VERSION 5.7 ;
  NOWIREEXTENSIONATPIN ON ;
  DIVIDERCHAR "/" ;
  BUSBITCHARS "[]" ;
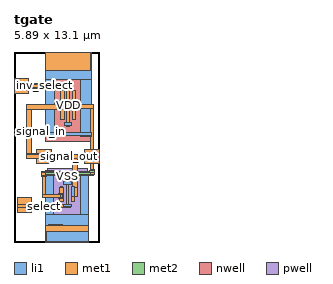
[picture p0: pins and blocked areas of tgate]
MACRO tgate
  CLASS BLOCK ;
  FOREIGN tgate ;
  ORIGIN 0.000 9.990 ;
  SIZE 5.890 BY 13.100 ;
  PIN inv_select
    ANTENNAGATEAREA 1.000000 ;
    PORT
      LAYER li1 ;
        RECT 3.480 0.690 3.980 0.860 ;
        RECT 3.480 -1.950 3.980 -1.780 ;
      LAYER met1 ;
        RECT 0.000 0.945 1.000 1.270 ;
        RECT 0.000 0.890 3.825 0.945 ;
        RECT 0.000 0.660 3.960 0.890 ;
        RECT 0.000 0.595 3.840 0.660 ;
        RECT 0.000 0.270 1.000 0.595 ;
        RECT 3.610 -1.750 3.840 0.595 ;
        RECT 3.500 -1.980 3.960 -1.750 ;
        RECT 3.610 -2.010 3.840 -1.980 ;
    END
  END inv_select
  PIN signal_in
    ANTENNADIFFAREA 0.870000 ;
    PORT
      LAYER li1 ;
        RECT 3.250 -1.565 3.420 0.475 ;
        RECT 3.990 -7.230 4.160 -6.190 ;
      LAYER met1 ;
        RECT 3.220 -0.495 3.450 0.455 ;
        RECT 0.885 -0.850 3.450 -0.495 ;
        RECT 0.885 -3.910 1.240 -0.850 ;
        RECT 3.220 -1.545 3.450 -0.850 ;
        RECT 1.570 -3.910 2.570 -3.590 ;
        RECT 0.885 -3.940 2.570 -3.910 ;
        RECT 0.885 -4.240 4.350 -3.940 ;
        RECT 0.885 -4.265 2.570 -4.240 ;
        RECT 1.570 -4.590 2.570 -4.265 ;
        RECT 4.050 -6.210 4.350 -4.240 ;
        RECT 3.960 -6.850 4.350 -6.210 ;
        RECT 3.960 -7.210 4.190 -6.850 ;
    END
  END signal_in
  PIN signal_out
    ANTENNADIFFAREA 0.870000 ;
    PORT
      LAYER li1 ;
        RECT 4.040 -1.565 4.210 0.475 ;
        RECT 3.200 -7.230 3.370 -6.190 ;
      LAYER met1 ;
        RECT 4.010 -0.505 4.240 0.455 ;
        RECT 4.010 -0.755 5.515 -0.505 ;
        RECT 4.010 -1.545 4.240 -0.755 ;
        RECT 5.265 -3.600 5.515 -0.755 ;
        RECT 4.890 -4.600 5.890 -3.600 ;
        RECT 5.295 -5.025 5.490 -4.600 ;
        RECT 1.920 -5.470 2.180 -5.150 ;
        RECT 5.265 -5.345 5.525 -5.025 ;
        RECT 1.950 -6.725 2.150 -5.470 ;
        RECT 3.170 -6.670 3.400 -6.210 ;
        RECT 3.070 -6.725 3.400 -6.670 ;
        RECT 1.950 -6.925 3.400 -6.725 ;
        RECT 3.070 -6.980 3.400 -6.925 ;
        RECT 3.170 -7.210 3.400 -6.980 ;
      LAYER met2 ;
        RECT 1.890 -5.210 2.210 -5.180 ;
        RECT 5.235 -5.210 5.555 -5.055 ;
        RECT 1.890 -5.315 5.555 -5.210 ;
        RECT 1.890 -5.410 5.480 -5.315 ;
        RECT 1.890 -5.440 2.210 -5.410 ;
    END
  END signal_out
  PIN select
    ANTENNAGATEAREA 0.500000 ;
    PORT
      LAYER li1 ;
        RECT 3.430 -6.020 3.930 -5.850 ;
        RECT 3.430 -7.570 3.930 -7.400 ;
      LAYER met1 ;
        RECT 3.450 -6.050 3.910 -5.820 ;
        RECT 0.220 -7.405 1.220 -6.930 ;
        RECT 3.620 -7.370 3.760 -6.050 ;
        RECT 3.450 -7.405 3.910 -7.370 ;
        RECT 0.220 -7.635 3.915 -7.405 ;
        RECT 0.220 -7.930 1.220 -7.635 ;
    END
  END select
  PIN VDD
    ANTENNADIFFAREA 3.567000 ;
    PORT
      LAYER nwell ;
        RECT 2.190 -3.030 5.270 1.940 ;
      LAYER li1 ;
        RECT 2.150 1.240 5.350 3.100 ;
        RECT 2.150 -2.470 2.790 1.240 ;
        RECT 4.580 -2.470 5.350 1.240 ;
        RECT 2.150 -2.640 5.350 -2.470 ;
        RECT 2.150 -2.730 2.790 -2.640 ;
        RECT 4.580 -2.700 5.350 -2.640 ;
        RECT 2.270 -2.750 2.790 -2.730 ;
        RECT 2.460 -2.760 2.790 -2.750 ;
      LAYER met1 ;
        RECT 2.140 1.820 5.300 3.110 ;
    END
  END VDD
  PIN VSS
    ANTENNADIFFAREA 2.946400 ;
    PORT
      LAYER pwell ;
        RECT 2.280 -8.500 5.080 -4.920 ;
      LAYER li1 ;
        RECT 2.200 -5.160 2.730 -5.060 ;
        RECT 4.610 -5.160 5.140 -5.100 ;
        RECT 2.200 -5.330 5.140 -5.160 ;
        RECT 2.200 -8.090 2.730 -5.330 ;
        RECT 4.610 -8.090 5.140 -5.330 ;
        RECT 2.200 -9.250 5.140 -8.090 ;
        RECT 2.210 -9.980 5.140 -9.250 ;
      LAYER met1 ;
        RECT 2.370 -8.870 3.370 -8.810 ;
        RECT 2.170 -9.990 5.140 -8.870 ;
    END
  END VSS
END tgate
END LIBRARY

